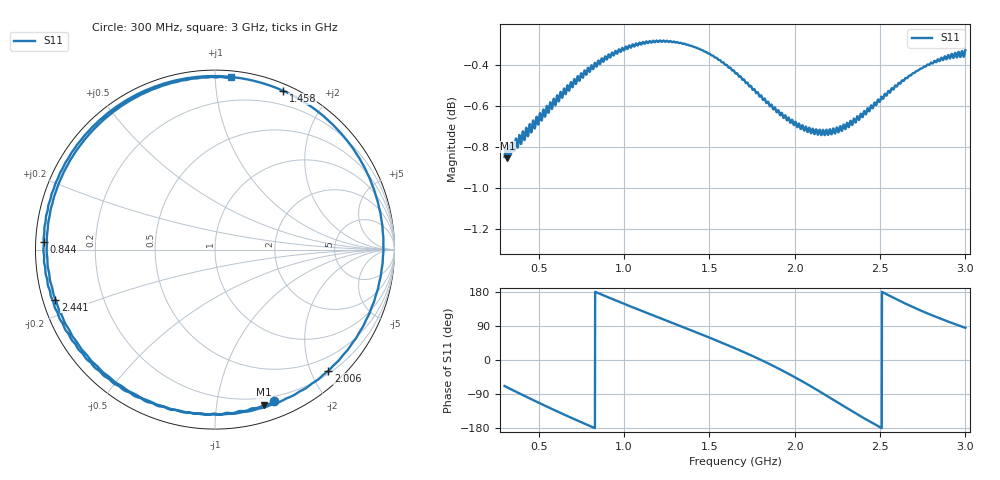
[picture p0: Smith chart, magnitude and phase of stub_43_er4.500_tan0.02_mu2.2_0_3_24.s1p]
! Chirptenna · simulación 3D de un stub abierto
# HZ S RI R 50
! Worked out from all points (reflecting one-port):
!   2001 points, 300 MHz to 3 GHz, reference 50 ohm
!   lowest |S11| = -0.9 dB at 316.2 MHz (marker M1), VSWR 20.35, Z = 7 - j67.8 ohm
!   phase of S11 starts at -69 deg and turns -567 deg over the sweep
!   S11 on the Smith chart (normalised r, x): 300 MHz: 0.15, -1.45; 844 MHz: 0.02, +0.02; 1.458 GHz: 0.06, +1.52; 2.006 GHz: 0.24, -2.28; 2.441 GHz: 0.04, -0.15; 3 GHz: 0.04, +1.09
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3e8  0.3302 -0.8447
3.162e8  0.2733 -0.8642
3.9585e8  -0.00316 -0.9136
4.755e8  -0.2787 -0.8785
6.375e8  -0.7353 -0.5815
7.401e8  -0.902 -0.2878
8.4405e8  -0.9547 0.0423
9.75e8  -0.8556 0.4407
1.14645e9  -0.5109 0.8214
1.3125e9  -0.0432 0.9662
1.4583e9  0.3814 0.8841
1.55145e9  0.6199 0.73
1.65e9  0.8151 0.4894
1.7391e9  0.9183 0.2176
1.82955e9  0.9309 -0.0942
1.91055e9  0.8493 -0.3771
1.9875e9  0.6848 -0.6225
2.0064e9  0.6316 -0.6755
2.0955e9  0.3188 -0.862
2.17245e9  -0.00616 -0.9187
2.2521e9  -0.3475 -0.8523
2.325e9  -0.6187 -0.6878
2.4411e9  -0.8888 -0.2783
2.54235e9  -0.9316 0.1224
2.6625e9  -0.7842 0.533
2.7462e9  -0.5992 0.7412
2.82855e9  -0.3835 0.8761
3e9  0.0865 0.9589
